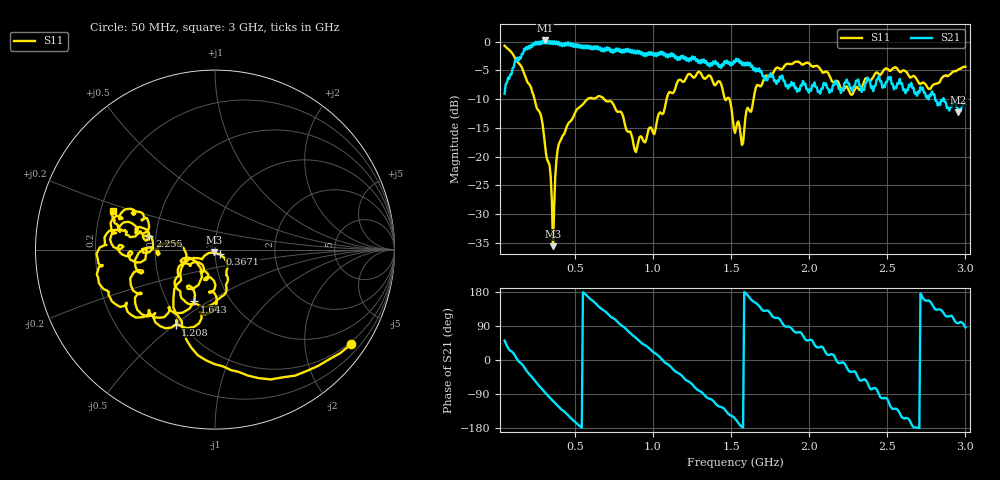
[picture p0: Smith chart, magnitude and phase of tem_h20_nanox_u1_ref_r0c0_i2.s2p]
! nanovna_capture.py 2026-10-26T21:50:18+0900
! NanoVNA-F_V2 fw 0.6.0 SN 4A3639384505514B
! cal: load open short thru cal'ed  over 50000000-3000000000 Hz, 201 points
! points 401, avg 4
! TEM h=20, genuine Nano X, 0 deg, centred, interleaved run G2
# HZ S RI R 50
! S12 and S22 are not measured (written as 0)
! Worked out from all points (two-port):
!   401 points, 50 MHz to 3 GHz, reference 50 ohm
!   highest |S21| = 0.24 dB at 308.1 MHz (marker M1); lowest = -12.3 dB at 2.956 GHz (marker M2)
!   |S21| within 3 dB of the highest: 130.9336 MHz to 131.3487 MHz (415.1 kHz wide, 0.317 % of centre); 154.6 MHz to 1.14 GHz (985.6 MHz wide, 152 % of centre) (the widest 2 of 10)
!   lowest |S11| = -35.6 dB at 359.8 MHz (marker M3), VSWR 1.03, Z = 49.5 - j1.57 ohm
!   |S11| at or under -10 dB: 241.6 MHz to 580.9 MHz (339.2 MHz wide, 82.5 % of centre); 687.1 MHz to 1.087 GHz (400.1 MHz wide, 45.1 % of centre); 1.489 GHz to 1.644 GHz (154.5 MHz wide, 9.86 % of centre) (the widest 3 of 4)
!   S12 and S22 are empty: the file has one direction only
!   S11 on the Smith chart (normalised r, x): 50 MHz: 0.44, -3.14; 367.1 MHz: 1.05, -0.05; 1.208 GHz: 0.47, -0.50; 1.643 GHz: 0.68, -0.44; 2.255 GHz: 0.46, +0.08; 3 GHz: 0.25, +0.17
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5e7  0.759 -0.5262  0.2224 0.2744  0 0  0 0
1.01625e8  0.3106 -0.7232  0.5539 0.2036  0 0  0 0
1.75375e8  -0.1588 -0.5037  0.8273 -0.2823  0 0  0 0
3.08125e8  -0.1185 -0.0462  0.0791 -1.024  0 0  0 0
3.5975e8  -0.00482 -0.0158  -0.2971 -0.9068  0 0  0 0
3.67125e8  0.0258 -0.0255  -0.3679 -0.9433  0 0  0 0
4.04e8  0.0637 -0.119  -0.5593 -0.7426  0 0  0 0
5.44125e8  0.0148 -0.2786  -0.9289 -0.0179  0 0  0 0
7.80125e8  -0.1983 -0.1457  -0.1124 0.8638  0 0  0 0
8.9075e8  -0.0697 -0.0842  0.4088 0.6751  0 0  0 0
1.03825e9  -0.0177 -0.2366  0.7551 0.132  0 0  0 0
1.207875e9  -0.2192 -0.4179  0.4558 -0.5775  0 0  0 0
1.370125e9  -0.4719 -0.1601  -0.1489 -0.6352  0 0  0 0
1.525e9  -0.1584 -0.0273  -0.5973 -0.2822  0 0  0 0
1.643e9  -0.1153 -0.2887  -0.5092 0.2456  0 0  0 0
1.827375e9  -0.4937 -0.309  -0.0624 0.5046  0 0  0 0
2.019125e9  -0.612 0.0267  0.2633 0.3277  0 0  0 0
2.255125e9  -0.365 0.0766  0.3798 -0.2112  0 0  0 0
2.51325e9  -0.5514 0.0944  -0.2104 -0.4244  0 0  0 0
2.712375e9  -0.3905 0.1769  -0.4035 0.0317  0 0  0 0
2.95575e9  -0.556 0.1454  -0.0311 0.2409  0 0  0 0
3e9  -0.5657 0.2156  0.0196 0.284  0 0  0 0
